VERSION 5.8 ;
BUSBITCHARS "[]" ;
DIVIDERCHAR "/" ;
UNITS
  DATABASE MICRONS 1000 ;
END UNITS

MANUFACTURINGGRID 0.05 ;

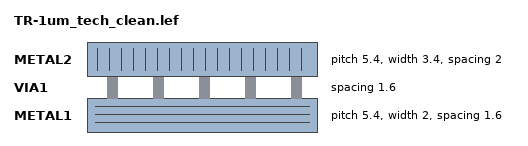
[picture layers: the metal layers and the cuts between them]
LAYER METAL1
  TYPE ROUTING ;
  DIRECTION HORIZONTAL ;
  PITCH 5.4 ;
  OFFSET 2.7 ;
  WIDTH 2.0 ;
  SPACING 1.6 ;
END METAL1

LAYER VIA1
  TYPE CUT ;
  SPACING 1.6 ;
END VIA1

LAYER METAL2
  TYPE ROUTING ;
  DIRECTION VERTICAL ;
  PITCH 5.4 ;
  OFFSET 2.7 ;
  WIDTH 3.4 ;
  SPACING 2.0 ;
END METAL2

VIA V1_1x1 DEFAULT
  LAYER METAL1 ;
    RECT -1.7 -1.7 1.7 1.7 ;
  LAYER VIA1 ;
    RECT -0.7 -0.7 0.7 0.7 ;
  LAYER METAL2 ;
    RECT -1.7 -1.7 1.7 1.7 ;
END V1_1x1

SITE TR1UM
  CLASS CORE ;
  SYMMETRY Y ;
  SIZE 5.4 BY 59.4 ;
END TR1UM

END LIBRARY
